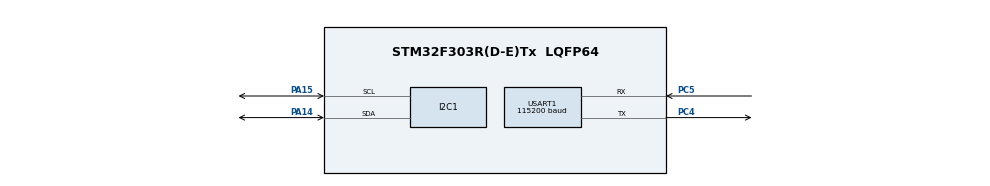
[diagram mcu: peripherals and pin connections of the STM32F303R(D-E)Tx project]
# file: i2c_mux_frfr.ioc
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I2C1.Timing=0x00201D2B
Mcu.Family=STM32F3
Mcu.Name=STM32F303R(D-E)Tx
Mcu.Package=LQFP64
NVIC.I2C1_ER_IRQn=true\:0\:0\:false\:false\:true\:true\:true\:true
NVIC.I2C1_EV_IRQn=true\:0\:0\:false\:false\:true\:true\:true\:true
NVIC.PriorityGroup=NVIC_PRIORITYGROUP_4
PA14.GPIO_Pu=GPIO_PULLUP
PA14.Mode=I2C
PA14.Signal=I2C1_SDA
PA15.GPIO_Pu=GPIO_PULLUP
PA15.Mode=I2C
PA15.Signal=I2C1_SCL
PC14-OSC32_IN.Mode=LSE-External-Oscillator
PC14-OSC32_IN.Signal=RCC_OSC32_IN
PC15-OSC32_OUT.Mode=LSE-External-Oscillator
PC15-OSC32_OUT.Signal=RCC_OSC32_OUT
PC4.Mode=Asynchronous
PC4.Signal=USART1_TX
PC5.Mode=Asynchronous
PC5.Signal=USART1_RX
PF0-OSC_IN.Mode=HSE-External-Oscillator
PF0-OSC_IN.Signal=RCC_OSC_IN
PF1-OSC_OUT.Mode=HSE-External-Oscillator
PF1-OSC_OUT.Signal=RCC_OSC_OUT
ProjectManager.HeapSize=0x200
ProjectManager.StackSize=0x400
ProjectManager.TargetToolchain=STM32CubeIDE
RCC.AHBFreq_Value=16000000
RCC.APB1Freq_Value=16000000
RCC.APB1TimFreq_Value=16000000
RCC.APB2Freq_Value=16000000
RCC.APB2TimFreq_Value=16000000
RCC.CortexFreq_Value=16000000
RCC.HCLKFreq_Value=16000000
RCC.HSE_VALUE=8000000
RCC.HSI_VALUE=8000000
RCC.PLLMUL=RCC_PLL_MUL4
RCC.PLLSourceVirtual=RCC_PLLSOURCE_HSE
RCC.SYSCLKFreq_VALUE=16000000
RCC.SYSCLKSourceVirtual=RCC_SYSCLKSOURCE_PLLCLK
RCC.USBFreq_Value=16000000
USART1.BaudRate=115200
USART1.VirtualMode-Asynchronous=VM_ASYNC
board=custom

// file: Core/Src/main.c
/* USER CODE BEGIN Header */
/**
  ******************************************************************************
  * @file           : main.c
  * @brief          : Main program body
  ******************************************************************************
  * @attention
  *
  * Copyright (c) 2026 STMicroelectronics.
  * All rights reserved.
  *
  * This software is licensed under terms that can be found in the LICENSE file
  * in the root directory of this software component.
  * If no LICENSE file comes with this software, it is provided AS-IS.
  *
  ******************************************************************************
  */
/* USER CODE END Header */
#include "main.h"

/* USER CODE BEGIN PM */
#define TCA9548A_ADDRESS (0x70  << 1)
#define AS5600_ADDRESS (0x36  << 1)
#define AS5600_REG 0x0C

#define NUM_ENCODERS 1
/* USER CODE END PM */

I2C_HandleTypeDef hi2c1;

UART_HandleTypeDef huart1;

void SystemClock_Config(void);
static void MX_GPIO_Init(void);
static void MX_I2C1_Init(void);
static void MX_USART1_UART_Init(void);

/* USER CODE BEGIN 0 */
uint8_t TxData_buf[2*NUM_ENCODERS] = {0};
// uint8_t reg_addr = 0x0E; // The register we want to read
//uint16_t raw;
//void read_magnetic_encoder(void)
//{
//    uint8_t buf[2];
//
//    for (uint8_t i = 0; i < NUM_ENCODERS; i++)
//    {
//    	uint8_t data = (1 << i);
//		HAL_I2C_Master_Transmit(&hi2c1, TCA9548A_ADDRESS, &data, 1, HAL_MAX_DELAY);
//		HAL_Delay(3);
//
//        HAL_StatusTypeDef st = HAL_I2C_Mem_Read(&hi2c1, AS5600_ADDRESS, 0x0E, I2C_MEMADD_SIZE_8BIT, buf, 2, HAL_MAX_DELAY);
//
//        HAL_Delay(2);
//
//        if (st == HAL_OK) {
//			uint16_t raw = ((uint16_t)buf[0] << 8) | buf[1];
//
//			raw &= 0x0FFF;
//
//			uint16_t scaled = (raw * 36000U) >> 12; //don touch its correct, avoids float calculation, just calcualtes current * 100 as required
//
//			TxData_buf[2*i] = (scaled >> 8) & 0xFF;
//			TxData_buf[2*i + 1] = scaled & 0xFF;
//        }
//    }
//}

HAL_StatusTypeDef select_channel(uint8_t c) {
	uint8_t channel = 1 << c;
	return HAL_I2C_Master_Transmit(&hi2c1, TCA9548A_ADDRESS, &channel, 1, 100);
}

HAL_StatusTypeDef read_angle(uint8_t angle[2]) {
	HAL_StatusTypeDef status;

	status = HAL_I2C_Mem_Read(&hi2c1, AS5600_ADDRESS, AS5600_REG, I2C_MEMADD_SIZE_8BIT, angle, 2, 100);

	angle[0] &= 0x0F;

	return status;
}

void read_magnetic_encoder(void)
{

    for (uint8_t i = 0; i < NUM_ENCODERS; i++)
    {

    	if (select_channel(i)) {
    		if(read_angle(&TxData_buf[2*i])) {
    			HAL_Delay(5);
    		}
    	}
//        // --- ALTERNATIVE READ METHOD BEGIN ---
//
//        // Step A: "Dummy Write" - Tell AS5600 we want to look at register 0x0E
//        // We ignore the return value here slightly because if the device is there, it will ACK.
//        HAL_StatusTypeDef st_write = HAL_I2C_Master_Transmit(&hi2c1, AS5600_ADDRESS, &reg_addr, 1, 10);
//
//        // Small delay to let the bus settle
//        // HAL_Delay(1);
//
//        // Step B: "Receive" - Read 2 bytes from the current pointer location
//        HAL_StatusTypeDef st_read = HAL_I2C_Master_Receive(&hi2c1, AS5600_ADDRESS, buf, 2, 10);
//
//        // --- ALTERNATIVE READ METHOD END ---
//
//        // Check if BOTH steps succeeded (mostly Step B matters)
//        if (st_write == HAL_OK && st_read == HAL_OK) {
//			uint16_t raw = ((uint16_t)buf[0] << 8) | buf[1];
//			raw &= 0x0FFF;
//			uint16_t scaled = (uint16_t)((uint32_t)raw * 36000U >> 12);
//
//			TxData_buf[2*i] = (scaled >> 8) & 0xFF;
//			TxData_buf[2*i + 1] = scaled & 0xFF;
//        }
//        else {
//        	// Error: 0xFF 0xFF
//        	TxData_buf[2*i] = 0xFF;
//        	TxData_buf[2*i + 1] = 0xFF;
//        }
    }
}

/* USER CODE END 0 */

int main(void)
{

  /* MCU Configuration--------------------------------------------------------*/

  /* Reset of all peripherals, Initializes the Flash interface and the Systick. */
  HAL_Init();

  /* Configure the system clock */
  SystemClock_Config();

  /* Initialize all configured peripherals */
  MX_GPIO_Init();
  MX_I2C1_Init();
  MX_USART1_UART_Init();

  /* Infinite loop */
  /* USER CODE BEGIN WHILE */
  while (1)
  {
	  if(HAL_I2C_IsDeviceReady(&hi2c1, TCA9548A_ADDRESS, 10, 500) != HAL_OK) {
		  HAL_UART_Transmit(&huart1, (uint8_t *) 0x07FF, sizeof(TxData_buf), 100);
		  HAL_Delay(10);
		  continue;
	  }
	  read_magnetic_encoder();
	  HAL_UART_Transmit(&huart1, TxData_buf, sizeof(TxData_buf), 100);
	  HAL_Delay(10);
    /* USER CODE END WHILE */

  }
}

void SystemClock_Config(void)
{
  RCC_OscInitTypeDef RCC_OscInitStruct = {0};
  RCC_ClkInitTypeDef RCC_ClkInitStruct = {0};
  RCC_PeriphCLKInitTypeDef PeriphClkInit = {0};

  /** Initializes the RCC Oscillators according to the specified parameters
  * in the RCC_OscInitTypeDef structure.
  */
  RCC_OscInitStruct.OscillatorType = RCC_OSCILLATORTYPE_HSI|RCC_OSCILLATORTYPE_HSE;
  RCC_OscInitStruct.HSEState = RCC_HSE_ON;
  RCC_OscInitStruct.HSIState = RCC_HSI_ON;
  RCC_OscInitStruct.HSICalibrationValue = RCC_HSICALIBRATION_DEFAULT;
  RCC_OscInitStruct.PLL.PLLState = RCC_PLL_ON;
  RCC_OscInitStruct.PLL.PLLSource = RCC_PLLSOURCE_HSE;
  RCC_OscInitStruct.PLL.PLLMUL = RCC_PLL_MUL4;
  RCC_OscInitStruct.PLL.PREDIV = RCC_PREDIV_DIV1;
  if (HAL_RCC_OscConfig(&RCC_OscInitStruct) != HAL_OK)
  {
    Error_Handler();
  }

  /** Initializes the CPU, AHB and APB buses clocks
  */
  RCC_ClkInitStruct.ClockType = RCC_CLOCKTYPE_HCLK|RCC_CLOCKTYPE_SYSCLK
                              |RCC_CLOCKTYPE_PCLK1|RCC_CLOCKTYPE_PCLK2;
  RCC_ClkInitStruct.SYSCLKSource = RCC_SYSCLKSOURCE_PLLCLK;
  RCC_ClkInitStruct.AHBCLKDivider = RCC_SYSCLK_DIV1;
  RCC_ClkInitStruct.APB1CLKDivider = RCC_HCLK_DIV1;
  RCC_ClkInitStruct.APB2CLKDivider = RCC_HCLK_DIV1;

  if (HAL_RCC_ClockConfig(&RCC_ClkInitStruct, FLASH_LATENCY_0) != HAL_OK)
  {
    Error_Handler();
  }
  PeriphClkInit.PeriphClockSelection = RCC_PERIPHCLK_USART1|RCC_PERIPHCLK_I2C1;
  PeriphClkInit.Usart1ClockSelection = RCC_USART1CLKSOURCE_PCLK2;
  PeriphClkInit.I2c1ClockSelection = RCC_I2C1CLKSOURCE_HSI;
  if (HAL_RCCEx_PeriphCLKConfig(&PeriphClkInit) != HAL_OK)
  {
    Error_Handler();
  }
}

static void MX_I2C1_Init(void)
{

  hi2c1.Instance = I2C1;
  hi2c1.Init.Timing = 0x00201D2B;
  hi2c1.Init.OwnAddress1 = 0;
  hi2c1.Init.AddressingMode = I2C_ADDRESSINGMODE_7BIT;
  hi2c1.Init.DualAddressMode = I2C_DUALADDRESS_DISABLE;
  hi2c1.Init.OwnAddress2 = 0;
  hi2c1.Init.OwnAddress2Masks = I2C_OA2_NOMASK;
  hi2c1.Init.GeneralCallMode = I2C_GENERALCALL_DISABLE;
  hi2c1.Init.NoStretchMode = I2C_NOSTRETCH_DISABLE;
  if (HAL_I2C_Init(&hi2c1) != HAL_OK)
  {
    Error_Handler();
  }

  /** Configure Analogue filter
  */
  if (HAL_I2CEx_ConfigAnalogFilter(&hi2c1, I2C_ANALOGFILTER_ENABLE) != HAL_OK)
  {
    Error_Handler();
  }

  /** Configure Digital filter
  */
  if (HAL_I2CEx_ConfigDigitalFilter(&hi2c1, 0) != HAL_OK)
  {
    Error_Handler();
  }

}

static void MX_USART1_UART_Init(void)
{

  huart1.Instance = USART1;
  huart1.Init.BaudRate = 115200;
  huart1.Init.WordLength = UART_WORDLENGTH_8B;
  huart1.Init.StopBits = UART_STOPBITS_1;
  huart1.Init.Parity = UART_PARITY_NONE;
  huart1.Init.Mode = UART_MODE_TX_RX;
  huart1.Init.HwFlowCtl = UART_HWCONTROL_NONE;
  huart1.Init.OverSampling = UART_OVERSAMPLING_16;
  huart1.Init.OneBitSampling = UART_ONE_BIT_SAMPLE_DISABLE;
  huart1.AdvancedInit.AdvFeatureInit = UART_ADVFEATURE_NO_INIT;
  if (HAL_UART_Init(&huart1) != HAL_OK)
  {
    Error_Handler();
  }

}

static void MX_GPIO_Init(void)
{

  /* GPIO Ports Clock Enable */
  __HAL_RCC_GPIOC_CLK_ENABLE();
  __HAL_RCC_GPIOF_CLK_ENABLE();
  __HAL_RCC_GPIOA_CLK_ENABLE();

}

void Error_Handler(void)
{
  __disable_irq();
  while (1)
  {
  }
}
